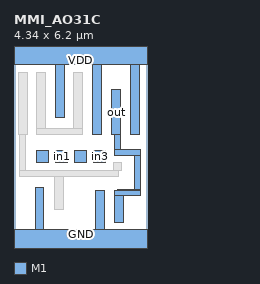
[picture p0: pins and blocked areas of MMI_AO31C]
MACRO MMI_AO31C
	CLASS CORE ;
	FOREIGN MMI_AO31C 0 0 ;
	SIZE 4.34 BY 6.2 ;
	SYMMETRY X Y ;
	SITE CORE1 ;
	PIN out
		DIRECTION output ;
		USE SIGNAL ;
		PORT
			LAYER M1 ;
			RECT 3.195 3.505 3.475 4.975 ;
			LAYER M1 ;
			RECT 3.285 3.03 3.475 3.505 ;
			LAYER M1 ;
			RECT 3.285 2.835 4.125 3.03 ;
			LAYER M1 ;
			RECT 3.935 1.7 4.125 2.835 ;
			LAYER M1 ;
			RECT 3.375 1.69 4.125 1.7 ;
			LAYER M1 ;
			RECT 3.295 1.51 4.125 1.69 ;
			LAYER M1 ;
			RECT 3.295 0.63 3.575 1.51 ;
		END
		AntennaDiffArea 1.309 ;
	END out
	PIN in1
		DIRECTION input ;
		USE SIGNAL ;
		PORT
			LAYER M1 ;
			RECT 1.36 2.6 1.74 2.98 ;
		END
		AntennaGateArea 0.546 ;
	END in1
	PIN GND
		DIRECTION inout ;
		USE GROUND ;
		PORT
			LAYER M1 ;
			RECT 0.695 0.42 0.975 1.77 ;
			LAYER M1 ;
			RECT 2.66 0.42 2.94 1.675 ;
			LAYER M1 ;
			RECT 0 -0.42 4.34 0.42 ;
		END
	END GND
	PIN in2
		DIRECTION input ;
		USE SIGNAL ;
		PORT
			LAYER M1 ;
			RECT 1.98 2.6 2.36 2.98 ;
		END
		AntennaGateArea 0.546 ;
	END in2
	PIN VDD
		DIRECTION inout ;
		USE POWER ;
		PORT
			LAYER M1 ;
			RECT 0 5.78 4.34 6.62 ;
			LAYER M1 ;
			RECT 1.365 4.065 1.645 5.78 ;
			LAYER M1 ;
			RECT 2.56 3.505 2.84 5.78 ;
			LAYER M1 ;
			RECT 3.8 3.505 4.08 5.78 ;
		END
	END VDD
	PIN in3
		DIRECTION input ;
		USE SIGNAL ;
		PORT
			LAYER M1 ;
			RECT 2.6 2.6 2.98 2.98 ;
		END
		AntennaGateArea 0.546 ;
	END in3
	PIN in0
		DIRECTION input ;
		USE SIGNAL ;
		PORT
			LAYER M1 ;
			RECT 0.74 2.6 1.12 2.98 ;
		END
		AntennaGateArea 0.39 ;
	END in0
	OBS
		LAYER M1 ;
		RECT 0.16 3.505 0.44 5.515 ;
		LAYER M1 ;
		RECT 0.75 3.695 1.03 5.515 ;
		LAYER M1 ;
		RECT 1.955 3.695 2.235 5.515 ;
		LAYER M1 ;
		RECT 0.75 3.505 2.235 3.695 ;
		LAYER M1 ;
		RECT 0.195 2.325 0.39 3.505 ;
		LAYER M1 ;
		RECT 3.235 2.33 3.515 2.61 ;
		LAYER M1 ;
		RECT 3.235 2.325 3.425 2.33 ;
		LAYER M1 ;
		RECT 0.195 2.135 3.425 2.325 ;
		LAYER M1 ;
		RECT 1.33 1.045 1.61 2.135 ;
	END
END MMI_AO31C
